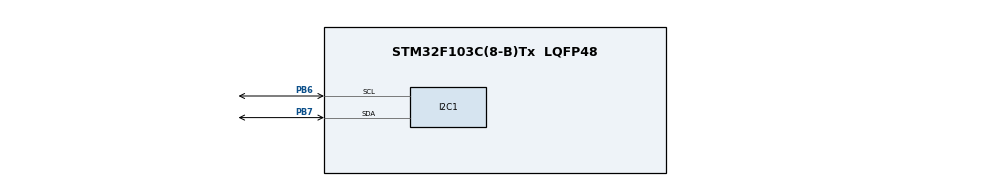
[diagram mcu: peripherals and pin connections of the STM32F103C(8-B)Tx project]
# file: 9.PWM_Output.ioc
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Mcu.Family=STM32F1
Mcu.Name=STM32F103C(8-B)Tx
Mcu.Package=LQFP48
NVIC.PriorityGroup=NVIC_PRIORITYGROUP_4
PA13.Mode=Serial_Wire
PA13.Signal=SYS_JTMS-SWDIO
PA14.Mode=Serial_Wire
PA14.Signal=SYS_JTCK-SWCLK
PB6.Mode=I2C
PB6.Signal=I2C1_SCL
PB7.Mode=I2C
PB7.Signal=I2C1_SDA
ProjectManager.HeapSize=0x200
ProjectManager.StackSize=0x400
ProjectManager.TargetToolchain=SW4STM32
RCC.APB1Freq_Value=8000000
RCC.APB2Freq_Value=8000000
RCC.SYSCLKSource=RCC_SYSCLKSOURCE_PLLCLK
board=custom

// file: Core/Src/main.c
/* USER CODE BEGIN Header */
/**
  ******************************************************************************
  * @file           : main.c
  * @brief          : Main program body
  ******************************************************************************
  * @attention
  *
  * Copyright (c) 2023 STMicroelectronics.
  * All rights reserved.
  *
  * This software is licensed under terms that can be found in the LICENSE file
  * in the root directory of this software component.
  * If no LICENSE file comes with this software, it is provided AS-IS.
  *
  ******************************************************************************
  */
/* USER CODE END Header */
#include "main.h"

/* USER CODE BEGIN Includes */
#include "led.h"
#include "gtim.h"
/* USER CODE END Includes */

 I2C_HandleTypeDef hi2c1;

void SystemClock_Config(void);
static void MX_GPIO_Init(void);
static void MX_I2C1_Init(void);

/* USER CODE BEGIN 0 */
extern TIM_HandleTypeDef g_timx_pwm_chy_handle;
/* USER CODE END 0 */

int main(void)
{
  /* USER CODE BEGIN 1 */
  uint16_t ledrpwmval = 0;
  uint8_t dir = 1;
  /* USER CODE END 1 */

  /* MCU Configuration--------------------------------------------------------*/

  /* Reset of all peripherals, Initializes the Flash interface and the Systick. */
  HAL_Init();

  /* USER CODE BEGIN Init */
  LED_Init();
  /* USER CODE END Init */

  /* Configure the system clock */
  SystemClock_Config();

  /* Initialize all configured peripherals */
  MX_GPIO_Init();
  MX_I2C1_Init();
  /* USER CODE BEGIN 2 */
  gtim_timx_pwm_chy_init(500 - 1, 72 - 1);/* 1Mhz鐨勮鏁伴鐜?,2Khz鐨凱WM. */
  /* USER CODE END 2 */

  /* Infinite loop */
  while (1)
  {
    HAL_Delay(10);

    if (dir)ledrpwmval++;
    /* dir==1 ledrpwmval 递增 */

    else ledrpwmval--;
    /* dir==0 ledrpwmval 递减 */

    if (ledrpwmval > 300)dir = 0;
    /* ledrpwmval 到达 300 后，方向为递减 */

    if (ledrpwmval == 0)dir = 1;
    /* ledrpwmval 递减到 0 后，方向改为递增 */
    /* 修改比较值控制占空比 */
    GTIM_TIMX_PWM_CHY_CCRX = ledrpwmval;
  }
}

void SystemClock_Config(void)
{
  RCC_OscInitTypeDef RCC_OscInitStruct = {0};
  RCC_ClkInitTypeDef RCC_ClkInitStruct = {0};

  /** Initializes the RCC Oscillators according to the specified parameters
  * in the RCC_OscInitTypeDef structure.
  */
  RCC_OscInitStruct.OscillatorType = RCC_OSCILLATORTYPE_HSI;
  RCC_OscInitStruct.HSIState = RCC_HSI_ON;
  RCC_OscInitStruct.HSICalibrationValue = RCC_HSICALIBRATION_DEFAULT;
  RCC_OscInitStruct.PLL.PLLState = RCC_PLL_NONE;
  if (HAL_RCC_OscConfig(&RCC_OscInitStruct) != HAL_OK)
  {
    Error_Handler();
  }

  /** Initializes the CPU, AHB and APB buses clocks
  */
  RCC_ClkInitStruct.ClockType = RCC_CLOCKTYPE_HCLK|RCC_CLOCKTYPE_SYSCLK
                              |RCC_CLOCKTYPE_PCLK1|RCC_CLOCKTYPE_PCLK2;
  RCC_ClkInitStruct.SYSCLKSource = RCC_SYSCLKSOURCE_HSI;
  RCC_ClkInitStruct.AHBCLKDivider = RCC_SYSCLK_DIV1;
  RCC_ClkInitStruct.APB1CLKDivider = RCC_HCLK_DIV1;
  RCC_ClkInitStruct.APB2CLKDivider = RCC_HCLK_DIV1;

  if (HAL_RCC_ClockConfig(&RCC_ClkInitStruct, FLASH_LATENCY_0) != HAL_OK)
  {
    Error_Handler();
  }
}

static void MX_I2C1_Init(void)
{

  hi2c1.Instance = I2C1;
  hi2c1.Init.ClockSpeed = 100000;
  hi2c1.Init.DutyCycle = I2C_DUTYCYCLE_2;
  hi2c1.Init.OwnAddress1 = 0;
  hi2c1.Init.AddressingMode = I2C_ADDRESSINGMODE_7BIT;
  hi2c1.Init.DualAddressMode = I2C_DUALADDRESS_DISABLE;
  hi2c1.Init.OwnAddress2 = 0;
  hi2c1.Init.GeneralCallMode = I2C_GENERALCALL_DISABLE;
  hi2c1.Init.NoStretchMode = I2C_NOSTRETCH_DISABLE;
  if (HAL_I2C_Init(&hi2c1) != HAL_OK)
  {
    Error_Handler();
  }

}

static void MX_GPIO_Init(void)
{

  /* GPIO Ports Clock Enable */
  __HAL_RCC_GPIOA_CLK_ENABLE();
  __HAL_RCC_GPIOB_CLK_ENABLE();

}

void Error_Handler(void)
{
  __disable_irq();
  while (1)
  {
  }
}
